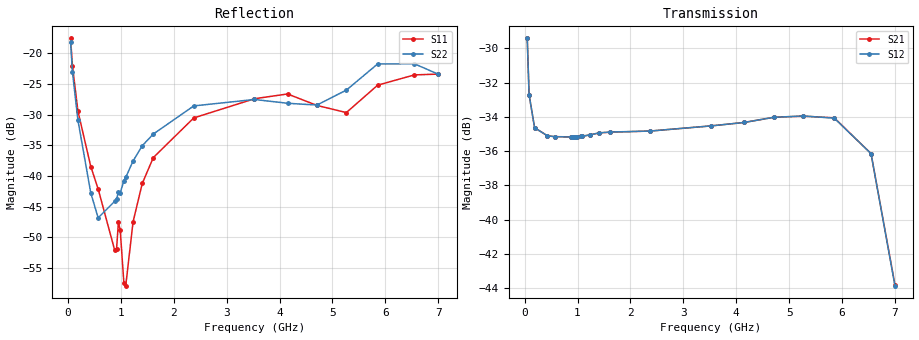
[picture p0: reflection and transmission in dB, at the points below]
! Integrated Device Technology
! Corporate Headquarters
! 6024 Silver Creek Valley Road
! San Jose, CA 95138  USA
! Phone:  1-408-284-8200
! Toll Free:  1-800-223-1366
! Webpage:  http://www.idt.com/
! Timing and RF Division
! 515 Groton Road, Suite 102
! Westford, MA 01886-6024
! Device:  F2258
! Description: Voltage Variable RF Attenuator
! Frequency:  50.0 -  6000.00 MHz
! Package:  3x3 mm Thin QFN Plastic Package: 16 pin
! Ports:  2 RF, 2 DC
!  Pin  1  = NC
!  Pin  2  = NC
!  Pin  3  = RF2  = Port 2
!  Pin  4  = GND
!  Pin  5  = Vdd
!  Pin  6  = NC
!  Pin  7  = VCTRL
!  Pin  8  = NC
!  Pin  9  = GND
!  Pin 10  = RF1  = Port 1
!  Pin 11  = NC
!  Pin 12  = NC
!  Pin 13  = NC
!  Pin 14  = NC
!  Pin 15  = NC
!  Pin 16  = NC
! Vcntrl:  2.070 Volts
! Vdd:  +3.300 Volts
! Current:  1.154 mA
! Data:  The device was measured on a the F2258 evaluation board which has
!  individual transmission lines to the RF pins.  Data was collected
!  using a calibrated network analyzer.  The evaluation board was
!  de-embedded using a TRL calibration technique.
!  The reference plane is the edge of the package pin.
! Misc:  SN 10
!  Action Tracker AT0285
! Date Measured:  2014-12-10
! Date:  2016-01-13  MJV
! Note:
!  Integrated Device Technology supplies this data as a sample of measured
!  data at the package pin for this product.  Your particular data for this
!  product may vary.
!  Data was taken at 25 degrees C.
!  Integrated Device Technology reserves the right to change this data at anytime.
!Freq_(GHz)  S11M_(dB)  S11P_(deg)  S21M_(dB)  S21P_(deg)  S12M_(dB)  S12P_(deg)  S22M_(dB)  S22P_(deg)
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# GHz S dB R 50
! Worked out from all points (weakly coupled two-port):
!   201 points, 50 MHz to 7 GHz, reference 50 ohm
!   highest |S21| = -29.42 dB at 50 MHz (marker M1); lowest = -43.8 dB at 7 GHz (marker M2)
!   lowest |S11| = -57.9 dB at 1.093 GHz (marker M3), VSWR 1.00, Z = 49.9 + j0.113 ohm
!   |S11| at or under -10 dB: start of sweep to end of sweep
!   |S22| runs from -47.3 to -18.2 dB; largest |S21 - S12| = 7.9e-05
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0.05  -17.55 -111.0  -29.42 -67.4  -29.42 -67.4  -18.22 -109.5
0.08475  -21.98 -107.4  -32.70 -47.8  -32.70 -47.8  -23.01 -102.7
0.189  -29.43 -109.4  -34.64 -24.3  -34.64 -24.3  -30.91 -95.8
0.43225  -38.47 -119.7  -35.11 -12.3  -35.11 -12.3  -42.79 -67.6
0.57125  -42.12 -124.6  -35.16 -10.3  -35.16 -10.3  -46.83 -22.9
0.884  -52.12 165.8  -35.17 -8.5  -35.18 -8.6  -44.13 43.0
0.91875  -51.97 150.2  -35.17 -8.5  -35.17 -8.5  -43.78 44.8
0.9535  -47.57 -162.7  -35.18 -8.4  -35.18 -8.4  -42.69 73.0
0.98825  -48.80 -173.7  -35.16 -8.3  -35.16 -8.3  -42.76 69.0
1.05775  -57.52 155.2  -35.14 -8.2  -35.14 -8.2  -40.77 57.6
1.0925  -57.90 117.7  -35.13 -8.1  -35.13 -8.1  -40.23 55.8
1.2315  -47.46 47.2  -35.06 -8.2  -35.06 -8.2  -37.54 44.0
1.40525  -41.21 33.7  -34.94 -8.9  -34.94 -8.9  -35.06 40.3
1.61375  -37.00 32.7  -34.90 -10.0  -34.89 -9.9  -33.16 33.5
2.37825  -30.53 48.1  -34.83 -13.7  -34.83 -13.7  -28.57 31.8
3.525  -27.40 91.6  -34.53 -20.3  -34.53 -20.3  -27.52 58.7
4.1505  -26.62 105.0  -34.33 -24.8  -34.33 -24.8  -28.14 68.0
4.7065  -28.49 95.6  -34.03 -29.5  -34.03 -29.5  -28.43 50.3
5.2625  -29.66 54.3  -33.96 -35.6  -33.95 -35.6  -25.99 13.1
5.85325  -25.19 29.8  -34.06 -46.1  -34.08 -46.1  -21.73 -7.4
6.54825  -23.51 45.0  -36.15 -66.5  -36.15 -66.4  -21.70 -41.7
7  -23.38 84.4  -43.80 -62.2  -43.86 -61.7  -23.40 -128.6
